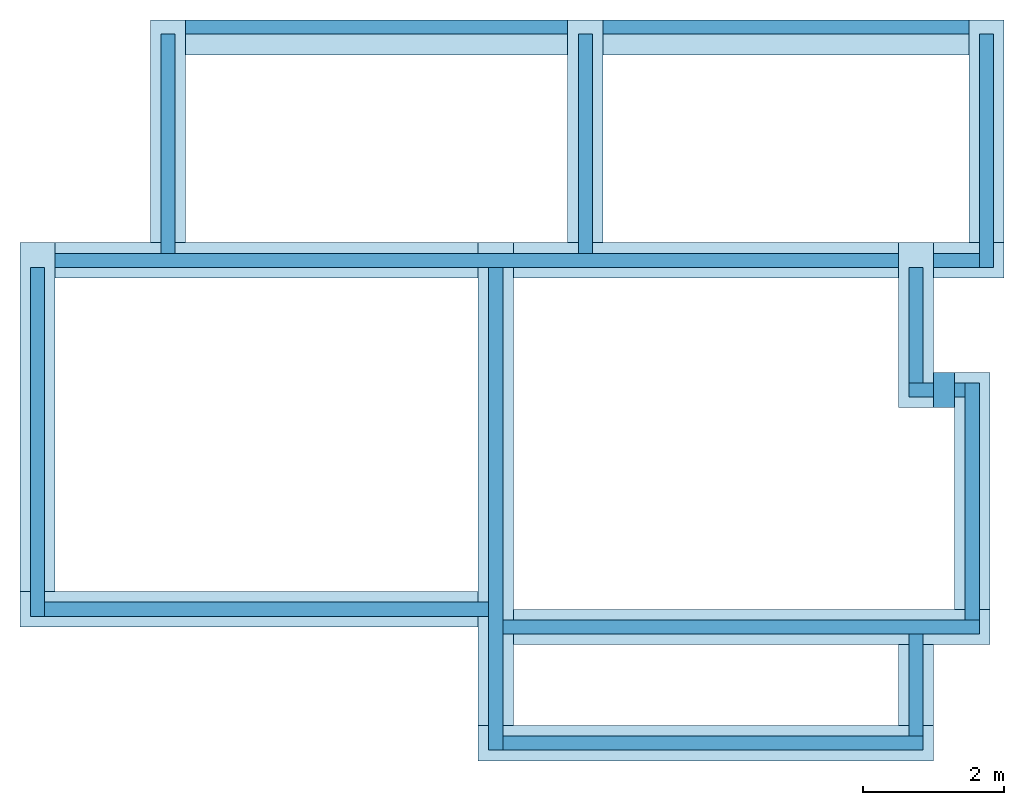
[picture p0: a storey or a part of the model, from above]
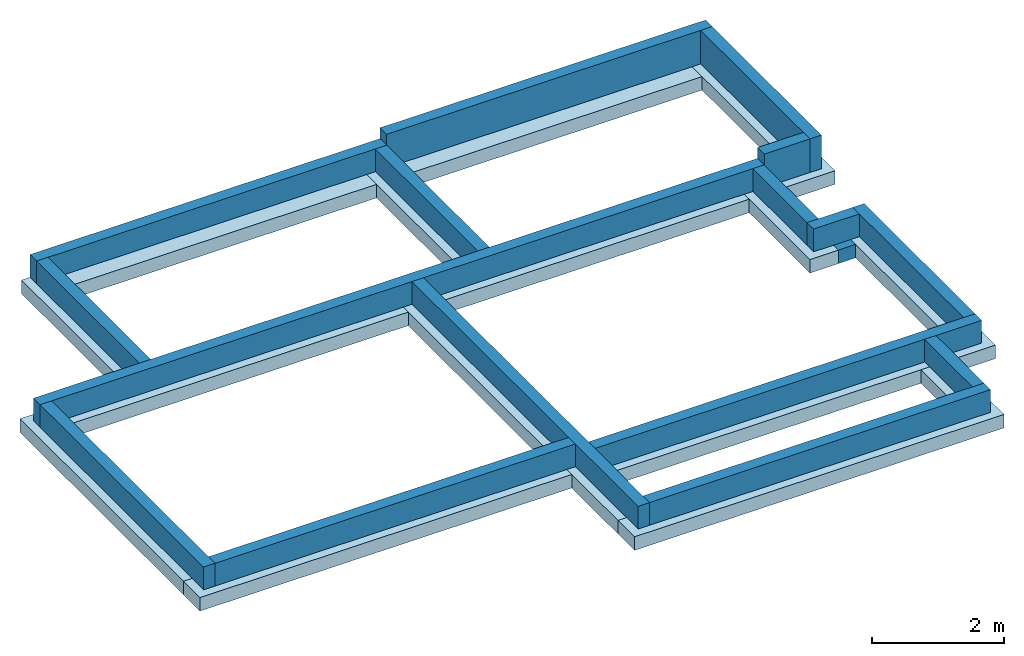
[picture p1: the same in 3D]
Properties of the parts of a building model (IFC2X3)

# File
Description: ViewDefinition [CoordinationView_V2.0], ExchangeRequirement [Architecture]
File name: Numéro du projet
Time: 2023-08-29T16:30:15+01:00
Written by: ODA SDAI 22.12
Made in: 23.0.11.19 - Exporter 23.0.11.19 - Interface utilisateur alternative 23.0.11.19

# IfcProject, Numéro du projet
LongName: Nom du projet; Phase: Etat du projet

# IfcSite, Default
RefLatitude: 48, 51, 23, 999633; RefLongitude: 2, 21, 3, 553905; RefElevation: 0 cm

# IfcBuilding
Pset_BuildingCommon - NumberOfStoreys: 4

# IfcBuildingStorey: Niveau:Ligne du Niveau (4)
Name | LongName | Elevation (cm)
0_Fondation | 0_Fondation | -70
-0.08_Dessus plancher | -0.08_Dessus plancher | -8
1_Rez-de-chaussée | 1_Rez-de-chaussée | -7.93413e-11
x_Arase | x_Arase | 270

# IfcDoor: Garage sectionnelle:240 x 200, Garage sectionnelle:240 x 200:294324
In: 1_Rez-de-chaussée
Type - OperationType: ROLLINGUP; ParameterTakesPrecedence: no; Sizeable: no; Material: Plastique - Noir, Peinture - Grise (2), Verre (3)
Type - Garage sectionnelle:240 x 200:294324:1 - PanelOperation: ROLLINGUP
Type - Pset_DoorCommon - IsExternal: yes
OverallHeight: 201.5 cm; OverallWidth: 243 cm
Pset_DoorCommon - Reference: 240 x 200
Pset_QuantityTakeOff - Reference: 240 x 200

# IfcDoor: Int. Simple:PP (0.83m x 2.04m), Int. Simple:PP (0.83m x 2.04m):290174
In: 1_Rez-de-chaussée
Type - ParameterTakesPrecedence: no; Sizeable: no; Material: Finition Peinture - Blanc satiné (4), Bois - Panneau de porte, Bois - Cadre de porte (3)
Type - Pset_DoorCommon - IsExternal: no; ThermalTransmittance: 3.7021 kg/K/s3
OverallHeight: 207.5 cm; OverallWidth: 90 cm
Pset_DoorCommon - Reference: PP (0.83m x 2.04m)
Pset_QuantityTakeOff - Reference: PP (0.83m x 2.04m)

# IfcDoor: Int. Simple:PP (0.90m x 2.10m) (5)
In: 1_Rez-de-chaussée
Type - ParameterTakesPrecedence: no; Sizeable: no; Material: Finition Peinture - Blanc satiné (4), Bois - Panneau de porte, Bois - Cadre de porte (3)
Type - Pset_DoorCommon - IsExternal: no
OverallHeight: 213.5 cm; OverallWidth: 97 cm
Pset_DoorCommon - Reference: PP (0.90m x 2.10m)
Pset_QuantityTakeOff - Reference: PP (0.90m x 2.10m)
Name (Int. Simple:PP (0.90m x 2.10m):...) | Material
296959
296989 | Finition Peinture - Blanc satiné, Bois - Panneau de porte, Bois - Cadre de porte
297018 | Finition Peinture - Blanc satiné, Bois - Panneau de porte, Bois - Cadre de porte
297040 | Finition Peinture - Blanc satiné, Bois - Panneau de porte, Bois - Cadre de porte
297064 | Finition Peinture - Blanc satiné, Bois - Panneau de porte, Bois - Cadre de porte

# IfcDoor: Porte d'entrée gris:90 x 205 cm, Porte d'entrée gris:90 x 205 cm:290112
In: 1_Rez-de-chaussée
Type - ParameterTakesPrecedence: no; Sizeable: no; Classification: B2030130 Exterior Glazed Doors - Wood (Uniformat); Material: Zinc (14), Wood, Cherry - Grain Vertical (5)
Type - Pset_DoorCommon - IsExternal: no
Type - Pset_ManufacturerTypeInformation - Manufacturer: Karona , Inc.
OverallHeight: 208.81 cm; OverallWidth: 97.62 cm
Pset_DoorCommon - Reference: 90 x 205 cm
Pset_QuantityTakeOff - Reference: 90 x 205 cm

# IfcFooting: Semelle filante:Semelle 50/25 (13)
In: 0_Fondation
PredefinedType: STRIP_FOOTING; Material: Béton - Béton coulé sur place
Pset_QuantityTakeOff - Reference: Semelle 50/25; sets with these values: 3
Name (Semelle filante:Semelle 50/25:...)
281321
281335
281349
281363
281377
281391
281405
281419
281433
281453
292528
292541
292554

# IfcFooting: Semelle filante:Semelle mitoyen, Semelle filante:Semelle mitoyen:292567
In: 0_Fondation
PredefinedType: STRIP_FOOTING; Material: Béton - Béton coulé sur place
Pset_QuantityTakeOff - Reference: Semelle mitoyen; sets with these values: 3

# IfcOpeningElement: Opening (34)
In: -0.08_Dessus plancher
Name | Reference | sets with these values
Mur de base:Mur 20:277076 | PP (0.90m x 2.10m) | 2
Mur de base:Mur 20:277612 | 0.90 m x 1.15 m | 2
Mur de base:Mur 20:277787 | 0.50 m x 0.85 m | 2
2 x Mur de base:Mur 20:277910 | 0.90 m x 1.15 m | 2
Mur de base:Mur 20:277961 | 0.60 m x 2.05 m | 2
Mur de base:Mur 20:278324 | 90 x 205 cm | 2
Mur de base:Mur 20:278701 | 1.00 m x 0.95 m | 2
Mur de base:Enduit 2:284451 | 0.90 m x 1.15 m | 2
Mur de base:Enduit 2:284878 | 0.50 m x 0.85 m | 2
2 x Mur de base:Enduit 2:285010 | 0.90 m x 1.15 m | 2
Mur de base:Enduit 2:285188 | 0.60 m x 2.05 m | 2
Mur de base:Enduit 2:285824 | 1.00 m x 0.95 m | 2
Mur de base:Enduit 2:286063 | 90 x 205 cm | 2
Mur de base:Enduit 2:286488 | 240 x 200 | 2
Mur de base:Doublage 14:287011 | PP (0.90m x 2.10m) | 2
Mur de base:Doublage 14:287133 | PP (0.83m x 2.04m) | 2
Mur de base:Cloison 7cm:295933 | PP (0.90m x 2.10m) | 2
Mur de base:Cloison 7cm:296090 | PP (0.90m x 2.10m) | 2
Mur de base:Mur 20:276848
Int. Simple:PP (0.83m x 2.04m):290174:1
Porte d'entrée gris:90 x 205 cm:290112:1
Mur de base:Doublage 14:287606
Mur de base:Doublage 14:288235
2 x Mur de base:Doublage 14:288408
Mur de base:Doublage 14:288623
Mur de base:Doublage 14:288945
Int. Simple:PP (0.90m x 2.10m):296959:1
Int. Simple:PP (0.90m x 2.10m):296989:1
Int. Simple:PP (0.90m x 2.10m):297018:1
Int. Simple:PP (0.90m x 2.10m):297040:1
Int. Simple:PP (0.90m x 2.10m):297064:1

# IfcRoof: Toit de base:Toit ardoise - 100 mm, Toit de base:Toit ardoise - 100 mm:292754
In: x_Arase
Material: Ardoise 10 cm
Pset_QuantityTakeOff - Reference: Toit ardoise - 100 mm
Pset_RoofCommon - IsExternal: yes; Reference: Toit ardoise - 100 mm; ProjectedArea: 131.332 m2; TotalArea: 160.326 m2

# IfcSlab: Sol:Dallage partie garage, Sol:Dallage partie garage:290550
In: 1_Rez-de-chaussée
Type - PredefinedType: FLOOR; Material: Maçonnerie - Béton 12 cm, Forme par défaut 55 cm
Type - Pset_SlabCommon - IsExternal: no
Pset_QuantityTakeOff - Reference: Dallage partie garage; sets with these values: 2
Pset_SlabCommon - LoadBearing: no; Reference: Dallage partie garage; PitchAngle: 0 deg

# IfcSlab: Sol:Dalle en béton - 200 mm, Sol:Dalle en béton - 200 mm:290711
In: -0.08_Dessus plancher
Type - PredefinedType: FLOOR; Material: Maçonnerie - Béton 20 cm
Type - Pset_SlabCommon - IsExternal: no
Pset_QuantityTakeOff - Reference: Dalle en béton - 200 mm; sets with these values: 2
Pset_SlabCommon - LoadBearing: no; PitchAngle: 0 deg; Reference: Dalle en béton - 200 mm

# IfcSlab: Toit de base:Toit ardoise - 100 mm (9)
In: x_Arase
Type - PredefinedType: ROOF
Type - Pset_SlabCommon - IsExternal: yes; ThermalTransmittance: 18.83 kg/K/s3
Material: Ardoise 10 cm
Pset_QuantityTakeOff - Reference: Toit ardoise - 100 mm; sets with these values: 2
Pset_SlabCommon - Reference: Toit ardoise - 100 mm; PitchAngle: 35 deg

# IfcWallStandardCase: Mur de base:Cloison 7cm (19)
In: -0.08_Dessus plancher
Type - PredefinedType: STANDARD; Material: Mur par défaut 7 cm
Type - Pset_WallCommon - IsExternal: no
Pset_QuantityTakeOff - Reference: Cloison 7cm; sets with these values: 2
Pset_WallCommon - ExtendToStructure: no; LoadBearing: no; Reference: Cloison 7cm
Name (Mur de base:Cloison 7cm:...)
295336
295377
295440
295556
295630
295811
295881
295933
296005
296042
296090
296222
296283
296320
296385
296426
296486
296515
296563

# IfcWallStandardCase: Mur de base:Doublage 14 (14)
In: -0.08_Dessus plancher
Type - PredefinedType: STANDARD; Material: Isolant rigide 14 cm
Type - Pset_WallCommon - IsExternal: yes; ThermalTransmittance: 0.25 kg/K/s3
Pset_QuantityTakeOff - Reference: Doublage 14; sets with these values: 2
Pset_WallCommon - ExtendToStructure: no; LoadBearing: no; Reference: Doublage 14
Name (Mur de base:Doublage 14:...)
286798
287011
287133
287252
287327
287606
287769
287860
288039
288235
288408
288623
288826
288945

# IfcWallStandardCase: Mur de base:Enduit 2 (14)
In: -0.08_Dessus plancher
Type - PredefinedType: STANDARD; Material: Maçonnerie - Enduit 2 cm
Type - Pset_WallCommon - IsExternal: yes
Pset_QuantityTakeOff - Reference: Enduit 2; sets with these values: 2
Pset_WallCommon - ExtendToStructure: no; LoadBearing: no; Reference: Enduit 2
Name (Mur de base:Enduit 2:...)
284299
284451
284706
284878
285010
285188
285410
285514
285643
285824
285911
286063
286195
286488

# IfcWallStandardCase: Mur de base:Mur 20 (30)
Type - PredefinedType: STANDARD; Material: Maçonnerie - Béton 20 cm
Type - Pset_WallCommon - IsExternal: yes
Pset_QuantityTakeOff - Reference: Mur 20; sets with these values: 2
Pset_WallCommon - Reference: Mur 20; LoadBearing: no
Name (Mur de base:Mur 20:...) | In | ExtendToStructure
276743 | -0.08_Dessus plancher | no
276848 | -0.08_Dessus plancher | no
277029 | -0.08_Dessus plancher | no
277076 | -0.08_Dessus plancher | no
277546 | -0.08_Dessus plancher | no
277612 | -0.08_Dessus plancher | no
277677 | -0.08_Dessus plancher | no
277787 | -0.08_Dessus plancher | no
277910 | -0.08_Dessus plancher | no
277961 | -0.08_Dessus plancher | no
278062 | -0.08_Dessus plancher | no
278324 | -0.08_Dessus plancher | no
278612 | -0.08_Dessus plancher | no
278641 | -0.08_Dessus plancher | no
278701 | -0.08_Dessus plancher | no
278748 | -0.08_Dessus plancher | no
279721 | 0_Fondation | yes
279860 | 0_Fondation | yes
280074 | 0_Fondation | yes
280163 | 0_Fondation | yes
280237 | 0_Fondation | yes
280356 | 0_Fondation | yes
280434 | 0_Fondation | yes
280511 | 0_Fondation | yes
280603 | 0_Fondation | yes
280661 | 0_Fondation | yes
280759 | 0_Fondation | yes
280858 | 0_Fondation | yes
281120 | 0_Fondation | yes
281282 | 0_Fondation | yes

# IfcWindow: 1 Vantail - Droit:0.50 m x 0.85 m, 1 Vantail - Droit:0.50 m x 0.85 m:289337
In: 1_Rez-de-chaussée
Type - ParameterTakesPrecedence: no; Sizeable: no; Material: Fenêtre - Poignée (2), Fenêtre - Appui (3), Fenêtre - Vitrage, Fenêtre - Cadre (3)
Type - Pset_WindowCommon - IsExternal: no
OverallHeight: 108 cm; OverallWidth: 60 cm
Pset_QuantityTakeOff - Reference: 0.50 m x 0.85 m
Pset_WindowCommon - IsExternal: yes; Reference: 0.50 m x 0.85 m

# IfcWindow: 1 Vantail - Droit:0.60 m x 2.05 m, 1 Vantail - Droit:0.60 m x 2.05 m:289744
In: 1_Rez-de-chaussée
Type - ParameterTakesPrecedence: no; Sizeable: no; Material: Fenêtre - Poignée (2), Fenêtre - Appui (3), Fenêtre - Vitrage, Fenêtre - Cadre (3)
Type - Pset_WindowCommon - IsExternal: no
OverallHeight: 218 cm; OverallWidth: 70 cm
Pset_QuantityTakeOff - Reference: 0.60 m x 2.05 m
Pset_WindowCommon - IsExternal: yes; Reference: 0.60 m x 2.05 m

# IfcWindow: 1 Vantail - Droit:0.90 m x 1.15 m (3)
In: 1_Rez-de-chaussée
Type - ParameterTakesPrecedence: no; Sizeable: no; Material: Fenêtre - Poignée (2), Fenêtre - Appui (3), Fenêtre - Vitrage, Fenêtre - Cadre (3)
Type - Pset_WindowCommon - IsExternal: no
OverallHeight: 128 cm; OverallWidth: 100 cm
Pset_QuantityTakeOff - Reference: 0.90 m x 1.15 m
Pset_WindowCommon - Reference: 0.90 m x 1.15 m
Name (1 Vantail - Droit:0.90 m x 1.15 m:...) | Material
289235 | Pset_WindowCommon - IsExternal: yes
289485 | Fenêtre - Poignée, Fenêtre - Appui, Fenêtre - Vitrage, Fenêtre - Cadre
289602 | Fenêtre - Poignée, Fenêtre - Appui, Fenêtre - Vitrage, Fenêtre - Cadre

# IfcWindow: 1 Vantail - Droit:1.00 m x 0.95 m, 1 Vantail - Droit:1.00 m x 0.95 m:289838
In: 1_Rez-de-chaussée
Type - ParameterTakesPrecedence: no; Sizeable: no; Material: Fenêtre - Poignée (2), Fenêtre - Appui (3), Fenêtre - Vitrage, Fenêtre - Cadre (3)
Type - Pset_WindowCommon - IsExternal: no
OverallHeight: 108 cm; OverallWidth: 110 cm
Pset_QuantityTakeOff - Reference: 1.00 m x 0.95 m
Pset_WindowCommon - IsExternal: yes; Reference: 1.00 m x 0.95 m
